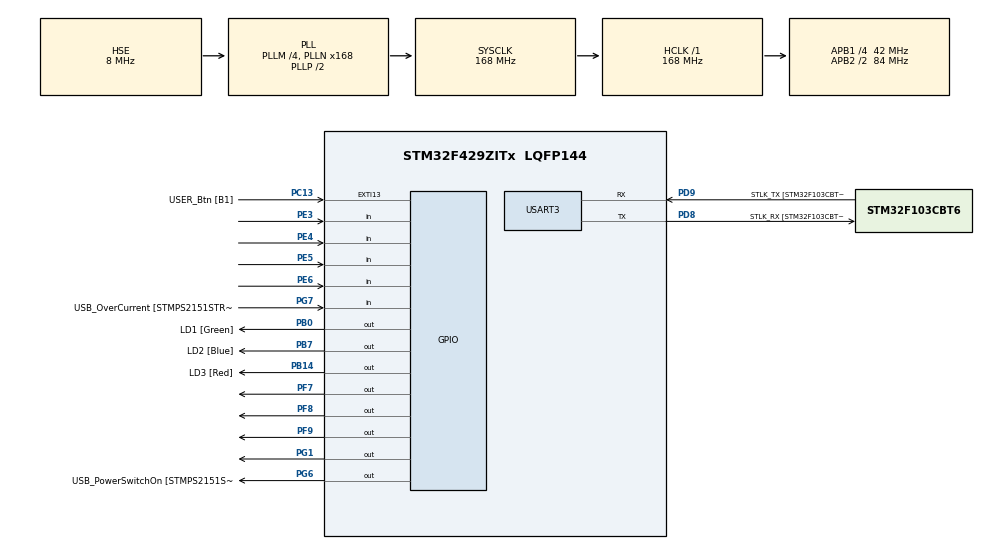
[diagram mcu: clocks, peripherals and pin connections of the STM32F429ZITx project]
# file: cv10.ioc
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Mcu.Family=STM32F4
Mcu.Name=STM32F429ZITx
Mcu.Package=LQFP144
NVIC.PriorityGroup=NVIC_PRIORITYGROUP_4
NVIC.TIM3_IRQn=true\:0\:0\:false\:false\:true\:true\:true\:true
PA1.GPIO_Label=RMII_REF_CLK [LAN8742A-CZ-TR_REFCLK0]
PA1.Signal=ETH_REF_CLK
PA10.GPIO_Label=USB_ID
PA10.Signal=USB_OTG_FS_ID
PA11.GPIO_Label=USB_DM
PA11.Signal=USB_OTG_FS_DM
PA12.GPIO_Label=USB_DP
PA12.Signal=USB_OTG_FS_DP
PA13.GPIO_Label=TMS
PA13.Mode=Serial_Wire
PA13.Signal=SYS_JTMS-SWDIO
PA14.GPIO_Label=TCK
PA14.Mode=Serial_Wire
PA14.Signal=SYS_JTCK-SWCLK
PA2.GPIO_Label=RMII_MDIO [LAN8742A-CZ-TR_MDIO]
PA2.Signal=ETH_MDIO
PA7.GPIO_Label=RMII_CRS_DV [LAN8742A-CZ-TR_CRS_DV]
PA7.Signal=ETH_CRS_DV
PA8.GPIO_Label=USB_SOF [TP1]
PA8.Signal=USB_OTG_FS_SOF
PA9.GPIO_Label=USB_VBUS
PA9.Signal=USB_OTG_FS_VBUS
PB0.GPIO_Label=LD1 [Green]
PB0.Signal=GPIO_Output
PB13.GPIO_Label=RMII_TXD1 [LAN8742A-CZ-TR_TXD1]
PB13.Signal=ETH_TXD1
PB14.GPIO_Label=LD3 [Red]
PB14.Signal=GPIO_Output
PB7.GPIO_Label=LD2 [Blue]
PB7.Signal=GPIO_Output
PC1.GPIO_Label=RMII_MDC [LAN8742A-CZ-TR_MDC]
PC1.Signal=ETH_MDC
PC13.GPIO_Label=USER_Btn [B1]
PC13.Signal=GPXTI13
PC14/OSC32_IN.Mode=LSE-External-Oscillator
PC14/OSC32_IN.Signal=RCC_OSC32_IN
PC15/OSC32_OUT.Mode=LSE-External-Oscillator
PC15/OSC32_OUT.Signal=RCC_OSC32_OUT
PC4.GPIO_Label=RMII_RXD0 [LAN8742A-CZ-TR_RXD0]
PC4.Signal=ETH_RXD0
PC5.GPIO_Label=RMII_RXD1 [LAN8742A-CZ-TR_RXD1]
PC5.Signal=ETH_RXD1
PD8.GPIO_Label=STLK_RX [STM32F103CBT6_PA3]
PD8.Mode=Asynchronous
PD8.Signal=USART3_TX
PD9.GPIO_Label=STLK_TX [STM32F103CBT6_PA2]
PD9.Mode=Asynchronous
PD9.Signal=USART3_RX
PE3.GPIO_PuPd=GPIO_PULLUP
PE3.Signal=GPIO_Input
PE4.GPIO_PuPd=GPIO_PULLUP
PE4.Signal=GPIO_Input
PE5.GPIO_PuPd=GPIO_PULLUP
PE5.Signal=GPIO_Input
PE6.GPIO_PuPd=GPIO_PULLUP
PE6.Signal=GPIO_Input
PF7.GPIO_ModeDefaultOutputPP=GPIO_MODE_OUTPUT_OD
PF7.GPIO_PuPd=GPIO_NOPULL
PF7.Signal=GPIO_Output
PF8.GPIO_ModeDefaultOutputPP=GPIO_MODE_OUTPUT_OD
PF8.GPIO_PuPd=GPIO_NOPULL
PF8.Signal=GPIO_Output
PF9.GPIO_ModeDefaultOutputPP=GPIO_MODE_OUTPUT_OD
PF9.GPIO_PuPd=GPIO_NOPULL
PF9.Signal=GPIO_Output
PG1.GPIO_ModeDefaultOutputPP=GPIO_MODE_OUTPUT_OD
PG1.GPIO_PuPd=GPIO_NOPULL
PG1.Signal=GPIO_Output
PG11.GPIO_Label=RMII_TX_EN [LAN8742A-CZ-TR_TXEN]
PG11.Signal=ETH_TX_EN
PG13.GPIO_Label=RMII_TXD0 [LAN8742A-CZ-TR_TXD0]
PG13.Signal=ETH_TXD0
PG6.GPIO_Label=USB_PowerSwitchOn [STMPS2151STR_EN]
PG6.Signal=GPIO_Output
PG7.GPIO_Label=USB_OverCurrent [STMPS2151STR_FAULT]
PG7.Signal=GPIO_Input
PH0/OSC_IN.GPIO_Label=MCO [STM32F103CBT6_PA8]
PH0/OSC_IN.Mode=HSE-External-Clock-Source
PH0/OSC_IN.Signal=RCC_OSC_IN
PH1/OSC_OUT.Mode=HSE-External-Clock-Source
PH1/OSC_OUT.Signal=RCC_OSC_OUT
ProjectManager.HeapSize=0x200
ProjectManager.StackSize=0x400
ProjectManager.TargetToolchain=STM32CubeIDE
RCC.48MHZClocksFreq_Value=48000000
RCC.AHBFreq_Value=168000000
RCC.APB1CLKDivider=RCC_HCLK_DIV4
RCC.APB1Freq_Value=42000000
RCC.APB1TimFreq_Value=84000000
RCC.APB2CLKDivider=RCC_HCLK_DIV2
RCC.APB2Freq_Value=84000000
RCC.APB2TimCLKDivider=2
RCC.APB2TimFreq_Value=168000000
RCC.CortexFreq_Value=168000000
RCC.HCLKFreq_Value=168000000
RCC.HSE_VALUE=8000000
RCC.HSI_VALUE=16000000
RCC.PLLM=4
RCC.PLLMUL=RCC_PLL_MUL9
RCC.PLLN=168
RCC.PLLQ=7
RCC.PLLSourceVirtual=RCC_PLLSOURCE_HSE
RCC.PRESCALERUSB=RCC_USBCLKSOURCE_PLL_DIV1_5
RCC.SYSCLKFreq_VALUE=168000000
RCC.SYSCLKSource=RCC_SYSCLKSOURCE_PLLCLK
RCC.SYSCLKSourceVirtual=RCC_SYSCLKSOURCE_PLLCLK
RCC.USBFreq_Value=48000000
RCC.VCOOutputFreq_Value=336000000
TIM3.AutoReloadPreload=TIM_AUTORELOAD_PRELOAD_ENABLE
TIM3.Period=99
TIM3.Prescaler=8399
USART3.VirtualMode=VM_ASYNC
VP_TIM3_VS_ClockSourceINT.Mode=Internal
board=NUCLEO-F429ZI

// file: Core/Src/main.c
/* USER CODE BEGIN Header */
/**
  ******************************************************************************
  * @file           : main.c
  * @brief          : Main program body
  ******************************************************************************
  * @attention
  *
  * Copyright (c) 2023 STMicroelectronics.
  * All rights reserved.
  *
  * This software is licensed under terms that can be found in the LICENSE file
  * in the root directory of this software component.
  * If no LICENSE file comes with this software, it is provided AS-IS.
  *
  ******************************************************************************
  */
/* USER CODE END Header */
#include "main.h"

/* USER CODE BEGIN Includes */
#include "stdio.h"
#include "stdint.h"
/* USER CODE END Includes */

/* USER CODE BEGIN PD */
#define PSSWDTIMEOUT 3000
/* USER CODE END PD */

TIM_HandleTypeDef htim3;

UART_HandleTypeDef huart3;

void SystemClock_Config(void);
static void MX_GPIO_Init(void);
static void MX_USART3_UART_Init(void);
static void MX_TIM3_Init(void);
/* USER CODE BEGIN PFP */
static volatile int8_t key = -1;
/* USER CODE END PFP */

/* USER CODE BEGIN 0 */
int __io_putchar(int ch)
{
	ITM_SendChar(ch);
	return 0;
}
/* USER CODE END 0 */

int main(void)
{

  /* MCU Configuration--------------------------------------------------------*/

  /* Reset of all peripherals, Initializes the Flash interface and the Systick. */
   HAL_Init();

  /* Configure the system clock */
  SystemClock_Config();

  /* Initialize all configured peripherals */
  MX_GPIO_Init();
  MX_USART3_UART_Init();
  MX_TIM3_Init();
  HAL_TIM_Base_Start_IT(&htim3);

  /* Infinite loop */
  /* USER CODE BEGIN WHILE */

  const int8_t code[] = {7,9,3,2,12};
  uint8_t pos = 0;
  uint8_t keyEntered = 0;
  uint32_t startTime = 0;
  printf(" Zadejte kod:\n");

  while (1) {
	  /* USER CODE END WHILE */
	  /* USER CODE BEGIN 3 */

	  if (key != -1) {

		  if (keyEntered == 0) {
			  startTime = HAL_GetTick();
			  keyEntered = 1;
		  }

		  if (key == code[pos]) {
			  pos++;
			  if (pos == sizeof(code)) {
				  HAL_GPIO_TogglePin(LD1_GPIO_Port, LD1_Pin);
				  printf("Spravne heslo\n");
				  pos = 0;
				  keyEntered = 0;
			  }
		  } else {
			  pos = 0;
		  }

		  printf("code = %d > pos = %d\n", key, pos);
		  HAL_Delay(500);
		  key = -1;
	  }

	  if (keyEntered == 1 && (HAL_GetTick() - startTime) > 5000) {
		  printf("Cas vyprsel, zadavani se resetuje.\n");
		  pos = 0;
		  keyEntered = 0;
	  }
  }
  /* USER CODE END 3 */
}

void SystemClock_Config(void)
{
  RCC_OscInitTypeDef RCC_OscInitStruct = {0};
  RCC_ClkInitTypeDef RCC_ClkInitStruct = {0};

  /** Configure the main internal regulator output voltage
  */
  __HAL_RCC_PWR_CLK_ENABLE();
  __HAL_PWR_VOLTAGESCALING_CONFIG(PWR_REGULATOR_VOLTAGE_SCALE1);

  /** Initializes the RCC Oscillators according to the specified parameters
  * in the RCC_OscInitTypeDef structure.
  */
  RCC_OscInitStruct.OscillatorType = RCC_OSCILLATORTYPE_HSE;
  RCC_OscInitStruct.HSEState = RCC_HSE_BYPASS;
  RCC_OscInitStruct.PLL.PLLState = RCC_PLL_ON;
  RCC_OscInitStruct.PLL.PLLSource = RCC_PLLSOURCE_HSE;
  RCC_OscInitStruct.PLL.PLLM = 4;
  RCC_OscInitStruct.PLL.PLLN = 168;
  RCC_OscInitStruct.PLL.PLLP = RCC_PLLP_DIV2;
  RCC_OscInitStruct.PLL.PLLQ = 7;
  if (HAL_RCC_OscConfig(&RCC_OscInitStruct) != HAL_OK)
  {
    Error_Handler();
  }

  /** Initializes the CPU, AHB and APB buses clocks
  */
  RCC_ClkInitStruct.ClockType = RCC_CLOCKTYPE_HCLK|RCC_CLOCKTYPE_SYSCLK
                              |RCC_CLOCKTYPE_PCLK1|RCC_CLOCKTYPE_PCLK2;
  RCC_ClkInitStruct.SYSCLKSource = RCC_SYSCLKSOURCE_PLLCLK;
  RCC_ClkInitStruct.AHBCLKDivider = RCC_SYSCLK_DIV1;
  RCC_ClkInitStruct.APB1CLKDivider = RCC_HCLK_DIV4;
  RCC_ClkInitStruct.APB2CLKDivider = RCC_HCLK_DIV2;

  if (HAL_RCC_ClockConfig(&RCC_ClkInitStruct, FLASH_LATENCY_5) != HAL_OK)
  {
    Error_Handler();
  }
}

static void MX_TIM3_Init(void)
{

  TIM_ClockConfigTypeDef sClockSourceConfig = {0};
  TIM_MasterConfigTypeDef sMasterConfig = {0};

  htim3.Instance = TIM3;
  htim3.Init.Prescaler = 8399;
  htim3.Init.CounterMode = TIM_COUNTERMODE_UP;
  htim3.Init.Period = 99;
  htim3.Init.ClockDivision = TIM_CLOCKDIVISION_DIV1;
  htim3.Init.AutoReloadPreload = TIM_AUTORELOAD_PRELOAD_ENABLE;
  if (HAL_TIM_Base_Init(&htim3) != HAL_OK)
  {
    Error_Handler();
  }
  sClockSourceConfig.ClockSource = TIM_CLOCKSOURCE_INTERNAL;
  if (HAL_TIM_ConfigClockSource(&htim3, &sClockSourceConfig) != HAL_OK)
  {
    Error_Handler();
  }
  sMasterConfig.MasterOutputTrigger = TIM_TRGO_RESET;
  sMasterConfig.MasterSlaveMode = TIM_MASTERSLAVEMODE_DISABLE;
  if (HAL_TIMEx_MasterConfigSynchronization(&htim3, &sMasterConfig) != HAL_OK)
  {
    Error_Handler();
  }

}

static void MX_USART3_UART_Init(void)
{

  huart3.Instance = USART3;
  huart3.Init.BaudRate = 115200;
  huart3.Init.WordLength = UART_WORDLENGTH_8B;
  huart3.Init.StopBits = UART_STOPBITS_1;
  huart3.Init.Parity = UART_PARITY_NONE;
  huart3.Init.Mode = UART_MODE_TX_RX;
  huart3.Init.HwFlowCtl = UART_HWCONTROL_NONE;
  huart3.Init.OverSampling = UART_OVERSAMPLING_16;
  if (HAL_UART_Init(&huart3) != HAL_OK)
  {
    Error_Handler();
  }

}

static void MX_GPIO_Init(void)
{
  GPIO_InitTypeDef GPIO_InitStruct = {0};

  /* GPIO Ports Clock Enable */
  __HAL_RCC_GPIOE_CLK_ENABLE();
  __HAL_RCC_GPIOC_CLK_ENABLE();
  __HAL_RCC_GPIOF_CLK_ENABLE();
  __HAL_RCC_GPIOH_CLK_ENABLE();
  __HAL_RCC_GPIOA_CLK_ENABLE();
  __HAL_RCC_GPIOB_CLK_ENABLE();
  __HAL_RCC_GPIOG_CLK_ENABLE();
  __HAL_RCC_GPIOD_CLK_ENABLE();

  /*Configure GPIO pin Output Level */
  HAL_GPIO_WritePin(GPIOF, Row3_Pin|Row4_Pin|Row2_Pin, GPIO_PIN_RESET);

  /*Configure GPIO pin Output Level */
  HAL_GPIO_WritePin(GPIOB, LD1_Pin|LD3_Pin|LD2_Pin, GPIO_PIN_RESET);

  /*Configure GPIO pin Output Level */
  HAL_GPIO_WritePin(GPIOG, Row1_Pin|USB_PowerSwitchOn_Pin, GPIO_PIN_RESET);

  /*Configure GPIO pins : Col1_Pin Col4_Pin Col3_Pin Col2_Pin */
  GPIO_InitStruct.Pin = Col1_Pin|Col4_Pin|Col3_Pin|Col2_Pin;
  GPIO_InitStruct.Mode = GPIO_MODE_INPUT;
  GPIO_InitStruct.Pull = GPIO_PULLUP;
  HAL_GPIO_Init(GPIOE, &GPIO_InitStruct);

  /*Configure GPIO pin : USER_Btn_Pin */
  GPIO_InitStruct.Pin = USER_Btn_Pin;
  GPIO_InitStruct.Mode = GPIO_MODE_IT_RISING;
  GPIO_InitStruct.Pull = GPIO_NOPULL;
  HAL_GPIO_Init(USER_Btn_GPIO_Port, &GPIO_InitStruct);

  /*Configure GPIO pins : Row3_Pin Row4_Pin Row2_Pin */
  GPIO_InitStruct.Pin = Row3_Pin|Row4_Pin|Row2_Pin;
  GPIO_InitStruct.Mode = GPIO_MODE_OUTPUT_OD;
  GPIO_InitStruct.Pull = GPIO_NOPULL;
  GPIO_InitStruct.Speed = GPIO_SPEED_FREQ_LOW;
  HAL_GPIO_Init(GPIOF, &GPIO_InitStruct);

  /*Configure GPIO pins : RMII_MDC_Pin RMII_RXD0_Pin RMII_RXD1_Pin */
  GPIO_InitStruct.Pin = RMII_MDC_Pin|RMII_RXD0_Pin|RMII_RXD1_Pin;
  GPIO_InitStruct.Mode = GPIO_MODE_AF_PP;
  GPIO_InitStruct.Pull = GPIO_NOPULL;
  GPIO_InitStruct.Speed = GPIO_SPEED_FREQ_VERY_HIGH;
  GPIO_InitStruct.Alternate = GPIO_AF11_ETH;
  HAL_GPIO_Init(GPIOC, &GPIO_InitStruct);

  /*Configure GPIO pins : RMII_REF_CLK_Pin RMII_MDIO_Pin RMII_CRS_DV_Pin */
  GPIO_InitStruct.Pin = RMII_REF_CLK_Pin|RMII_MDIO_Pin|RMII_CRS_DV_Pin;
  GPIO_InitStruct.Mode = GPIO_MODE_AF_PP;
  GPIO_InitStruct.Pull = GPIO_NOPULL;
  GPIO_InitStruct.Speed = GPIO_SPEED_FREQ_VERY_HIGH;
  GPIO_InitStruct.Alternate = GPIO_AF11_ETH;
  HAL_GPIO_Init(GPIOA, &GPIO_InitStruct);

  /*Configure GPIO pins : LD1_Pin LD3_Pin LD2_Pin */
  GPIO_InitStruct.Pin = LD1_Pin|LD3_Pin|LD2_Pin;
  GPIO_InitStruct.Mode = GPIO_MODE_OUTPUT_PP;
  GPIO_InitStruct.Pull = GPIO_NOPULL;
  GPIO_InitStruct.Speed = GPIO_SPEED_FREQ_LOW;
  HAL_GPIO_Init(GPIOB, &GPIO_InitStruct);

  /*Configure GPIO pin : Row1_Pin */
  GPIO_InitStruct.Pin = Row1_Pin;
  GPIO_InitStruct.Mode = GPIO_MODE_OUTPUT_OD;
  GPIO_InitStruct.Pull = GPIO_NOPULL;
  GPIO_InitStruct.Speed = GPIO_SPEED_FREQ_LOW;
  HAL_GPIO_Init(Row1_GPIO_Port, &GPIO_InitStruct);

  /*Configure GPIO pin : RMII_TXD1_Pin */
  GPIO_InitStruct.Pin = RMII_TXD1_Pin;
  GPIO_InitStruct.Mode = GPIO_MODE_AF_PP;
  GPIO_InitStruct.Pull = GPIO_NOPULL;
  GPIO_InitStruct.Speed = GPIO_SPEED_FREQ_VERY_HIGH;
  GPIO_InitStruct.Alternate = GPIO_AF11_ETH;
  HAL_GPIO_Init(RMII_TXD1_GPIO_Port, &GPIO_InitStruct);

  /*Configure GPIO pin : USB_PowerSwitchOn_Pin */
  GPIO_InitStruct.Pin = USB_PowerSwitchOn_Pin;
  GPIO_InitStruct.Mode = GPIO_MODE_OUTPUT_PP;
  GPIO_InitStruct.Pull = GPIO_NOPULL;
  GPIO_InitStruct.Speed = GPIO_SPEED_FREQ_LOW;
  HAL_GPIO_Init(USB_PowerSwitchOn_GPIO_Port, &GPIO_InitStruct);

  /*Configure GPIO pin : USB_OverCurrent_Pin */
  GPIO_InitStruct.Pin = USB_OverCurrent_Pin;
  GPIO_InitStruct.Mode = GPIO_MODE_INPUT;
  GPIO_InitStruct.Pull = GPIO_NOPULL;
  HAL_GPIO_Init(USB_OverCurrent_GPIO_Port, &GPIO_InitStruct);

  /*Configure GPIO pins : USB_SOF_Pin USB_ID_Pin USB_DM_Pin USB_DP_Pin */
  GPIO_InitStruct.Pin = USB_SOF_Pin|USB_ID_Pin|USB_DM_Pin|USB_DP_Pin;
  GPIO_InitStruct.Mode = GPIO_MODE_AF_PP;
  GPIO_InitStruct.Pull = GPIO_NOPULL;
  GPIO_InitStruct.Speed = GPIO_SPEED_FREQ_VERY_HIGH;
  GPIO_InitStruct.Alternate = GPIO_AF10_OTG_FS;
  HAL_GPIO_Init(GPIOA, &GPIO_InitStruct);

  /*Configure GPIO pin : USB_VBUS_Pin */
  GPIO_InitStruct.Pin = USB_VBUS_Pin;
  GPIO_InitStruct.Mode = GPIO_MODE_INPUT;
  GPIO_InitStruct.Pull = GPIO_NOPULL;
  HAL_GPIO_Init(USB_VBUS_GPIO_Port, &GPIO_InitStruct);

  /*Configure GPIO pins : RMII_TX_EN_Pin RMII_TXD0_Pin */
  GPIO_InitStruct.Pin = RMII_TX_EN_Pin|RMII_TXD0_Pin;
  GPIO_InitStruct.Mode = GPIO_MODE_AF_PP;
  GPIO_InitStruct.Pull = GPIO_NOPULL;
  GPIO_InitStruct.Speed = GPIO_SPEED_FREQ_VERY_HIGH;
  GPIO_InitStruct.Alternate = GPIO_AF11_ETH;
  HAL_GPIO_Init(GPIOG, &GPIO_InitStruct);

}

/* USER CODE BEGIN 4 */
void HAL_TIM_PeriodElapsedCallback(TIM_HandleTypeDef *htim)
{
 static int row = 0;
 static const int keyboard[4][4] = {
 { 1, 2, 3, 21 },
 { 4, 5, 6, 22 },
 { 7, 8, 9, 23 },
 { 11, 0, 12, 24 },
 };
 if (key == -1) {
 if (HAL_GPIO_ReadPin(Col1_GPIO_Port, Col1_Pin) == GPIO_PIN_RESET) key = keyboard[row][0];
 if (HAL_GPIO_ReadPin(Col2_GPIO_Port, Col2_Pin) == GPIO_PIN_RESET) key = keyboard[row][1];
 if (HAL_GPIO_ReadPin(Col3_GPIO_Port, Col3_Pin) == GPIO_PIN_RESET) key = keyboard[row][2];
 if (HAL_GPIO_ReadPin(Col4_GPIO_Port, Col4_Pin) == GPIO_PIN_RESET) key = keyboard[row][3];
 }
 HAL_GPIO_WritePin(Row1_GPIO_Port, Row1_Pin, GPIO_PIN_SET);
 HAL_GPIO_WritePin(Row2_GPIO_Port, Row2_Pin, GPIO_PIN_SET);
 HAL_GPIO_WritePin(Row3_GPIO_Port, Row3_Pin, GPIO_PIN_SET);
 HAL_GPIO_WritePin(Row4_GPIO_Port, Row4_Pin, GPIO_PIN_SET);
 switch (row) {
 case 0: row = 1; HAL_GPIO_WritePin(Row2_GPIO_Port, Row2_Pin, GPIO_PIN_RESET); break;
 case 1: row = 2; HAL_GPIO_WritePin(Row3_GPIO_Port, Row3_Pin, GPIO_PIN_RESET); break;
 case 2: row = 3; HAL_GPIO_WritePin(Row4_GPIO_Port, Row4_Pin, GPIO_PIN_RESET); break;
 case 3: row = 0; HAL_GPIO_WritePin(Row1_GPIO_Port, Row1_Pin, GPIO_PIN_RESET); break;
 }

}
/* USER CODE END 4 */

void Error_Handler(void)
{
  __disable_irq();
  while (1)
  {
  }
}
